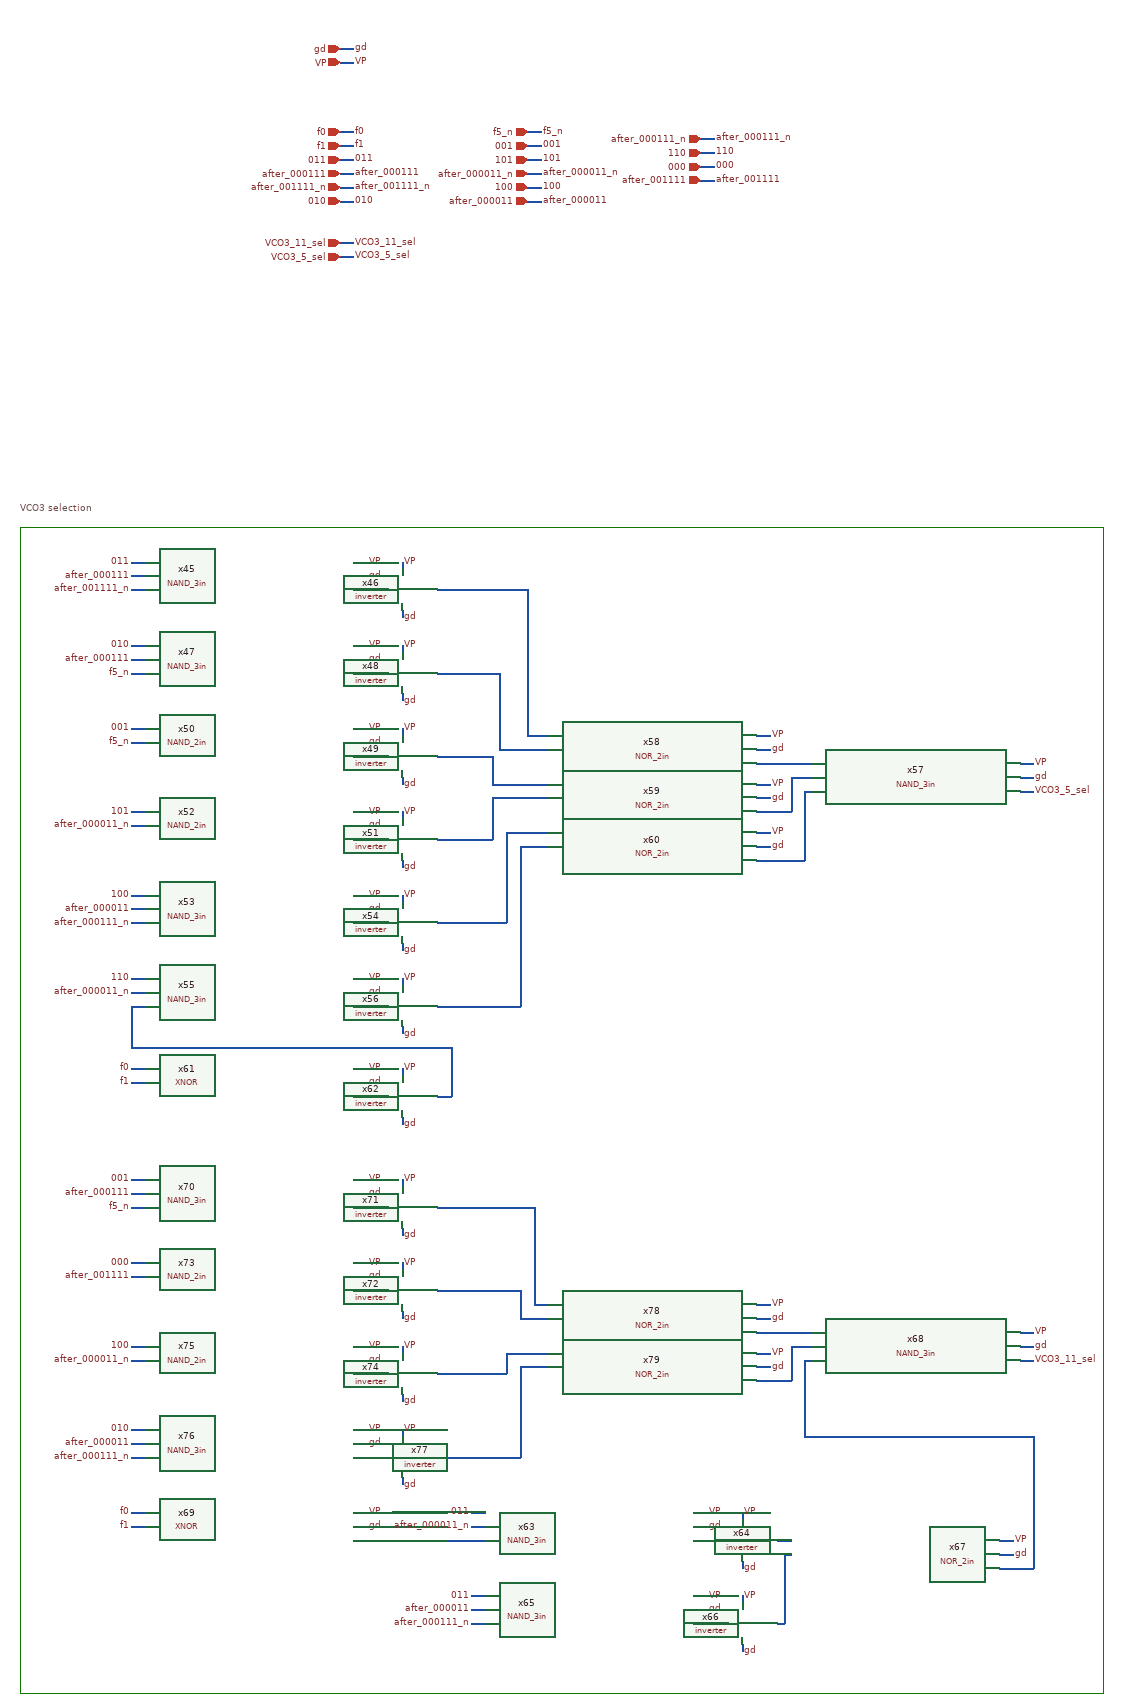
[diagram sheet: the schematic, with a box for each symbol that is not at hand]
v {xschem version=3.4.8RC file_version=1.3}
G {}
K {}
V {}
S {}
F {}
E {}
L 4 1210 -1360 1210 -1020 {}
L 4 1210 -1690 1210 -1350 {}
L 4 1210 -2030 1210 -1690 {}
L 4 1210 -2230 1210 -1890 {}
L 4 1210 -890 1210 -550 {}
L 4 1210 -1220 1210 -880 {}
L 4 1210 -1560 1210 -1220 {}
L 4 1210 -1760 1210 -1420 {}
L 4 2770 -2030 2770 -1690 {}
L 4 2770 -2230 2770 -1890 {}
L 4 2770 -890 2770 -550 {}
L 4 2770 -1220 2770 -880 {}
L 4 2770 -1560 2770 -1220 {}
L 4 2770 -1760 2770 -1420 {}
L 4 1210 -2230 1550 -2230 {}
L 4 1550 -2230 1890 -2230 {}
L 4 1880 -2230 2220 -2230 {}
L 4 2100 -2230 2440 -2230 {}
L 4 1540 -2230 1880 -2230 {}
L 4 1880 -2230 2220 -2230 {}
L 4 2210 -2230 2550 -2230 {}
L 4 2430 -2230 2770 -2230 {}
L 4 1210 -550 1550 -550 {}
L 4 1540 -550 1880 -550 {}
L 4 1880 -550 2220 -550 {}
L 4 2210 -550 2550 -550 {}
L 4 2430 -550 2770 -550 {}
T {VCO3 selection} 1210 -2270 0 0 0.4 0.4 {}
N 1690 -2160 1710 -2160 {lab=gd}
N 1690 -2180 1710 -2180 {lab=VP}
N 1760 -2110 1760 -2100 {lab=gd}
N 1760 -2180 1760 -2170 {lab=VP}
N 1690 -2140 1740 -2140 {lab=#net1}
N 1810 -2140 1940 -2140 {lab=#net2}
N 1370 -2180 1390 -2180 {lab=011}
N 1370 -2140 1390 -2140 {lab=after_001111_n}
N 1370 -2160 1390 -2160 {lab=after_000111}
N 1690 -2040 1710 -2040 {lab=gd}
N 1690 -2060 1710 -2060 {lab=VP}
N 1760 -1990 1760 -1980 {lab=gd}
N 1760 -2060 1760 -2050 {lab=VP}
N 1690 -2020 1740 -2020 {lab=#net3}
N 1810 -2020 1900 -2020 {lab=#net4}
N 1370 -2060 1390 -2060 {lab=010}
N 1370 -2020 1390 -2020 {lab=f5_n}
N 1370 -2040 1390 -2040 {lab=after_000111}
N 1690 -1920 1710 -1920 {lab=gd}
N 1690 -1940 1710 -1940 {lab=VP}
N 1760 -1870 1760 -1860 {lab=gd}
N 1760 -1940 1760 -1930 {lab=VP}
N 1690 -1900 1740 -1900 {lab=#net5}
N 1810 -1900 1890 -1900 {lab=#net6}
N 1370 -1940 1390 -1940 {lab=001}
N 1370 -1920 1390 -1920 {lab=f5_n}
N 1690 -1800 1710 -1800 {lab=gd}
N 1690 -1820 1710 -1820 {lab=VP}
N 1760 -1750 1760 -1740 {lab=gd}
N 1760 -1820 1760 -1810 {lab=VP}
N 1690 -1780 1740 -1780 {lab=#net7}
N 1810 -1780 1890 -1780 {lab=#net8}
N 1370 -1820 1390 -1820 {lab=101}
N 1370 -1800 1390 -1800 {lab=after_000011_n}
N 1690 -1680 1710 -1680 {lab=gd}
N 1690 -1700 1710 -1700 {lab=VP}
N 1760 -1630 1760 -1620 {lab=gd}
N 1760 -1700 1760 -1690 {lab=VP}
N 1690 -1660 1740 -1660 {lab=#net9}
N 1810 -1660 1910 -1660 {lab=#net10}
N 1370 -1700 1390 -1700 {lab=100}
N 1370 -1660 1390 -1660 {lab=after_000111_n}
N 1370 -1680 1390 -1680 {lab=after_000011}
N 1690 -1560 1710 -1560 {lab=gd}
N 1690 -1580 1710 -1580 {lab=VP}
N 1760 -1510 1760 -1500 {lab=gd}
N 1760 -1580 1760 -1570 {lab=VP}
N 1690 -1540 1740 -1540 {lab=#net11}
N 1370 -1580 1390 -1580 {lab=110}
N 1370 -1540 1390 -1540 {lab=#net12}
N 1370 -1560 1390 -1560 {lab=after_000011_n}
N 2270 -1910 2290 -1910 {lab=gd}
N 2270 -1930 2290 -1930 {lab=VP}
N 2270 -1840 2290 -1840 {lab=gd}
N 2270 -1860 2290 -1860 {lab=VP}
N 2270 -1770 2290 -1770 {lab=gd}
N 2270 -1790 2290 -1790 {lab=VP}
N 2650 -1870 2670 -1870 {lab=gd}
N 2650 -1890 2670 -1890 {lab=VP}
N 2270 -1890 2350 -1890 {lab=#net13}
N 2270 -1820 2320 -1820 {lab=#net14}
N 2320 -1870 2320 -1820 {lab=#net14}
N 2320 -1870 2350 -1870 {lab=#net14}
N 2340 -1850 2350 -1850 {lab=#net15}
N 2340 -1850 2340 -1750 {lab=#net15}
N 2270 -1750 2340 -1750 {lab=#net15}
N 2650 -1850 2670 -1850 {lab=VCO3_5_sel}
N 1890 -1860 1970 -1860 {lab=#net6}
N 1890 -1900 1890 -1860 {lab=#net6}
N 1890 -1840 1970 -1840 {lab=#net8}
N 1890 -1840 1890 -1780 {lab=#net8}
N 1910 -1790 1970 -1790 {lab=#net10}
N 1910 -1790 1910 -1660 {lab=#net10}
N 1810 -1540 1930 -1540 {lab=#net16}
N 1930 -1770 1930 -1540 {lab=#net16}
N 1930 -1770 1970 -1770 {lab=#net16}
N 1900 -1910 1970 -1910 {lab=#net4}
N 1900 -2020 1900 -1910 {lab=#net4}
N 1940 -2140 1940 -1930 {lab=#net2}
N 1940 -1930 1970 -1930 {lab=#net2}
N 1690 -1430 1710 -1430 {lab=gd}
N 1690 -1450 1710 -1450 {lab=VP}
N 1760 -1380 1760 -1370 {lab=gd}
N 1760 -1450 1760 -1440 {lab=VP}
N 1690 -1410 1740 -1410 {lab=#net17}
N 1810 -1410 1830 -1410 {lab=#net12}
N 1830 -1480 1830 -1410 {lab=#net12}
N 1370 -1480 1830 -1480 {lab=#net12}
N 1370 -1540 1370 -1480 {lab=#net12}
N 1370 -1450 1390 -1450 {lab=f0}
N 1370 -1430 1390 -1430 {lab=f1}
N 2180 -790 2200 -790 {lab=gd}
N 2180 -810 2200 -810 {lab=VP}
N 2250 -740 2250 -730 {lab=gd}
N 2250 -810 2250 -800 {lab=VP}
N 2180 -770 2230 -770 {lab=#net18}
N 2300 -770 2320 -770 {lab=#net19}
N 2180 -670 2200 -670 {lab=gd}
N 2180 -690 2200 -690 {lab=VP}
N 2250 -620 2250 -610 {lab=gd}
N 2250 -690 2250 -680 {lab=VP}
N 2180 -650 2230 -650 {lab=#net20}
N 2300 -650 2310 -650 {lab=#net21}
N 2620 -750 2640 -750 {lab=gd}
N 2620 -770 2640 -770 {lab=VP}
N 2620 -730 2670 -730 {lab=#net22}
N 2310 -750 2320 -750 {lab=#net21}
N 2310 -750 2310 -650 {lab=#net21}
N 1690 -790 1710 -790 {lab=gd}
N 1690 -810 1710 -810 {lab=VP}
N 1860 -690 1880 -690 {lab=011}
N 1860 -650 1880 -650 {lab=after_000111_n}
N 1860 -670 1880 -670 {lab=after_000011}
N 1370 -810 1390 -810 {lab=f0}
N 1370 -790 1390 -790 {lab=f1}
N 1860 -810 1880 -810 {lab=011}
N 1860 -790 1880 -790 {lab=after_000011_n}
N 1690 -770 1880 -770 {lab=#net23}
N 1690 -1270 1710 -1270 {lab=gd}
N 1690 -1290 1710 -1290 {lab=VP}
N 1760 -1220 1760 -1210 {lab=gd}
N 1760 -1290 1760 -1280 {lab=VP}
N 1690 -1250 1740 -1250 {lab=#net24}
N 1810 -1250 1950 -1250 {lab=#net25}
N 1370 -1290 1390 -1290 {lab=001}
N 1370 -1250 1390 -1250 {lab=f5_n}
N 1370 -1270 1390 -1270 {lab=after_000111}
N 1690 -1150 1710 -1150 {lab=gd}
N 1690 -1170 1710 -1170 {lab=VP}
N 1760 -1100 1760 -1090 {lab=gd}
N 1760 -1170 1760 -1160 {lab=VP}
N 1690 -1130 1740 -1130 {lab=#net26}
N 1810 -1130 1930 -1130 {lab=#net27}
N 1370 -1170 1390 -1170 {lab=000}
N 1370 -1150 1390 -1150 {lab=after_001111}
N 1690 -1030 1710 -1030 {lab=gd}
N 1690 -1050 1710 -1050 {lab=VP}
N 1760 -980 1760 -970 {lab=gd}
N 1760 -1050 1760 -1040 {lab=VP}
N 1690 -1010 1740 -1010 {lab=#net28}
N 1810 -1010 1910 -1010 {lab=#net29}
N 1370 -1050 1390 -1050 {lab=100}
N 1370 -1030 1390 -1030 {lab=after_000011_n}
N 1690 -910 1710 -910 {lab=gd}
N 1690 -930 1710 -930 {lab=VP}
N 1760 -860 1760 -850 {lab=gd}
N 1760 -930 1760 -920 {lab=VP}
N 1690 -890 1740 -890 {lab=#net30}
N 1810 -890 1930 -890 {lab=#net31}
N 1370 -930 1390 -930 {lab=010}
N 1370 -890 1390 -890 {lab=after_000111_n}
N 1370 -910 1390 -910 {lab=after_000011}
N 2270 -1090 2290 -1090 {lab=gd}
N 2270 -1110 2290 -1110 {lab=VP}
N 2270 -1020 2290 -1020 {lab=gd}
N 2270 -1040 2290 -1040 {lab=VP}
N 2650 -1050 2670 -1050 {lab=gd}
N 2650 -1070 2670 -1070 {lab=VP}
N 2270 -1070 2350 -1070 {lab=#net32}
N 2270 -1000 2320 -1000 {lab=#net33}
N 2320 -1050 2320 -1000 {lab=#net33}
N 2320 -1050 2350 -1050 {lab=#net33}
N 2340 -1030 2350 -1030 {lab=#net22}
N 2340 -1030 2340 -920 {lab=#net22}
N 2650 -1030 2670 -1030 {lab=VCO3_11_sel}
N 2670 -920 2670 -730 {lab=#net22}
N 2340 -920 2670 -920 {lab=#net22}
N 1950 -1250 1950 -1110 {lab=#net25}
N 1950 -1110 1970 -1110 {lab=#net25}
N 1930 -1090 1970 -1090 {lab=#net27}
N 1930 -1130 1930 -1090 {lab=#net27}
N 1910 -1040 1910 -1010 {lab=#net29}
N 1910 -1040 1970 -1040 {lab=#net29}
N 1930 -1020 1970 -1020 {lab=#net31}
N 1930 -1020 1930 -890 {lab=#net31}
N 1670 -2920 1690 -2920 {lab=gd}
N 1670 -2900 1690 -2900 {lab=VP}
N 1670 -2800 1690 -2800 {lab=f0}
N 1670 -2780 1690 -2780 {lab=f1}
N 1670 -2640 1690 -2640 {lab=VCO3_11_sel}
N 1670 -2620 1690 -2620 {lab=VCO3_5_sel}
N 1670 -2760 1690 -2760 {lab=011}
N 1670 -2740 1690 -2740 {lab=after_000111}
N 1670 -2720 1690 -2720 {lab=after_001111_n}
N 1670 -2700 1690 -2700 {lab=010}
N 1940 -2780 1960 -2780 {lab=001}
N 1940 -2760 1960 -2760 {lab=101}
N 1940 -2800 1960 -2800 {lab=f5_n}
N 1940 -2720 1960 -2720 {lab=100}
N 1940 -2700 1960 -2700 {lab=after_000011}
N 1940 -2740 1960 -2740 {lab=after_000011_n}
N 2190 -2770 2210 -2770 {lab=110}
N 2190 -2750 2210 -2750 {lab=000}
N 2190 -2790 2210 -2790 {lab=after_000111_n}
N 2190 -2730 2210 -2730 {lab=after_001111}
C {NAND_3in.sym} 1540 -2160 0 0 {name=x45}
C {lab_wire.sym} 1710 -2180 2 0 {name=p221 sig_type=std_logic lab=VP}
C {lab_wire.sym} 1710 -2160 2 0 {name=p222 sig_type=std_logic lab=gd}
C {inverter.sym} 1760 -2140 0 0 {name=x46}
C {lab_wire.sym} 1760 -2180 0 1 {name=p223 sig_type=std_logic lab=VP}
C {lab_wire.sym} 1760 -2100 2 0 {name=p224 sig_type=std_logic lab=gd}
C {NAND_3in.sym} 1540 -2040 0 0 {name=x47}
C {lab_wire.sym} 1710 -2060 2 0 {name=p225 sig_type=std_logic lab=VP}
C {lab_wire.sym} 1710 -2040 2 0 {name=p226 sig_type=std_logic lab=gd}
C {inverter.sym} 1760 -2020 0 0 {name=x48}
C {lab_wire.sym} 1760 -2060 0 1 {name=p227 sig_type=std_logic lab=VP}
C {lab_wire.sym} 1760 -1980 2 0 {name=p228 sig_type=std_logic lab=gd}
C {lab_wire.sym} 1710 -1940 2 0 {name=p229 sig_type=std_logic lab=VP}
C {lab_wire.sym} 1710 -1920 2 0 {name=p230 sig_type=std_logic lab=gd}
C {inverter.sym} 1760 -1900 0 0 {name=x49}
C {lab_wire.sym} 1760 -1940 0 1 {name=p231 sig_type=std_logic lab=VP}
C {lab_wire.sym} 1760 -1860 2 0 {name=p232 sig_type=std_logic lab=gd}
C {NAND_2in.sym} 1540 -1920 0 0 {name=x50}
C {lab_wire.sym} 1710 -1820 2 0 {name=p233 sig_type=std_logic lab=VP}
C {lab_wire.sym} 1710 -1800 2 0 {name=p234 sig_type=std_logic lab=gd}
C {inverter.sym} 1760 -1780 0 0 {name=x51}
C {lab_wire.sym} 1760 -1820 0 1 {name=p235 sig_type=std_logic lab=VP}
C {lab_wire.sym} 1760 -1740 2 0 {name=p236 sig_type=std_logic lab=gd}
C {NAND_2in.sym} 1540 -1800 0 0 {name=x52}
C {NAND_3in.sym} 1540 -1680 0 0 {name=x53}
C {lab_wire.sym} 1710 -1700 2 0 {name=p237 sig_type=std_logic lab=VP}
C {lab_wire.sym} 1710 -1680 2 0 {name=p238 sig_type=std_logic lab=gd}
C {inverter.sym} 1760 -1660 0 0 {name=x54}
C {lab_wire.sym} 1760 -1700 0 1 {name=p239 sig_type=std_logic lab=VP}
C {lab_wire.sym} 1760 -1620 2 0 {name=p240 sig_type=std_logic lab=gd}
C {NAND_3in.sym} 1540 -1560 0 0 {name=x55}
C {lab_wire.sym} 1710 -1580 2 0 {name=p241 sig_type=std_logic lab=VP}
C {lab_wire.sym} 1710 -1560 2 0 {name=p242 sig_type=std_logic lab=gd}
C {inverter.sym} 1760 -1540 0 0 {name=x56}
C {lab_wire.sym} 1760 -1580 0 1 {name=p243 sig_type=std_logic lab=VP}
C {lab_wire.sym} 1760 -1500 2 0 {name=p244 sig_type=std_logic lab=gd}
C {NAND_3in.sym} 2500 -1870 0 0 {name=x57}
C {NOR_2in.sym} 2120 -1910 0 0 {name=x58}
C {lab_wire.sym} 2290 -1930 2 0 {name=p245 sig_type=std_logic lab=VP}
C {lab_wire.sym} 2290 -1910 2 0 {name=p246 sig_type=std_logic lab=gd}
C {NOR_2in.sym} 2120 -1840 0 0 {name=x59}
C {lab_wire.sym} 2290 -1860 2 0 {name=p247 sig_type=std_logic lab=VP}
C {lab_wire.sym} 2290 -1840 2 0 {name=p248 sig_type=std_logic lab=gd}
C {NOR_2in.sym} 2120 -1770 0 0 {name=x60}
C {lab_wire.sym} 2290 -1790 2 0 {name=p249 sig_type=std_logic lab=VP}
C {lab_wire.sym} 2290 -1770 2 0 {name=p250 sig_type=std_logic lab=gd}
C {lab_wire.sym} 2670 -1890 2 0 {name=p251 sig_type=std_logic lab=VP}
C {lab_wire.sym} 2670 -1870 2 0 {name=p252 sig_type=std_logic lab=gd}
C {lab_wire.sym} 1370 -2180 0 0 {name=p253 sig_type=std_logic lab=011}
C {lab_wire.sym} 1370 -2060 0 0 {name=p254 sig_type=std_logic lab=010}
C {lab_wire.sym} 1370 -1940 0 0 {name=p255 sig_type=std_logic lab=001}
C {lab_wire.sym} 1370 -1820 0 0 {name=p256 sig_type=std_logic lab=101}
C {lab_wire.sym} 1370 -1580 0 0 {name=p257 sig_type=std_logic lab=110}
C {lab_wire.sym} 1370 -1700 0 0 {name=p258 sig_type=std_logic lab=100}
C {XNOR.sym} 1540 -1430 0 0 {name=x61}
C {lab_wire.sym} 1710 -1450 2 0 {name=p259 sig_type=std_logic lab=VP}
C {lab_wire.sym} 1710 -1430 2 0 {name=p260 sig_type=std_logic lab=gd}
C {inverter.sym} 1760 -1410 0 0 {name=x62}
C {lab_wire.sym} 1760 -1450 0 1 {name=p261 sig_type=std_logic lab=VP}
C {lab_wire.sym} 1760 -1370 2 0 {name=p262 sig_type=std_logic lab=gd}
C {lab_wire.sym} 1370 -2160 0 0 {name=p263 sig_type=std_logic lab=after_000111}
C {lab_wire.sym} 1370 -2140 0 0 {name=p264 sig_type=std_logic lab=after_001111_n}
C {lab_wire.sym} 1370 -2040 0 0 {name=p265 sig_type=std_logic lab=after_000111}
C {lab_wire.sym} 1370 -2020 0 0 {name=p266 sig_type=std_logic lab=f5_n}
C {lab_wire.sym} 1370 -1920 0 0 {name=p267 sig_type=std_logic lab=f5_n}
C {lab_wire.sym} 1370 -1800 0 0 {name=p268 sig_type=std_logic lab=after_000011_n}
C {lab_wire.sym} 1370 -1680 0 0 {name=p269 sig_type=std_logic lab=after_000011}
C {lab_wire.sym} 1370 -1660 0 0 {name=p270 sig_type=std_logic lab=after_000111_n}
C {lab_wire.sym} 1370 -1560 0 0 {name=p271 sig_type=std_logic lab=after_000011_n}
C {lab_wire.sym} 1370 -1450 0 0 {name=p272 sig_type=std_logic lab=f0}
C {lab_wire.sym} 1370 -1430 0 0 {name=p273 sig_type=std_logic lab=f1}
C {lab_wire.sym} 2670 -1850 2 0 {name=p274 sig_type=std_logic lab=VCO3_5_sel}
C {NAND_3in.sym} 2030 -790 0 0 {name=x63}
C {lab_wire.sym} 2200 -810 2 0 {name=p275 sig_type=std_logic lab=VP}
C {lab_wire.sym} 2200 -790 2 0 {name=p276 sig_type=std_logic lab=gd}
C {inverter.sym} 2250 -770 0 0 {name=x64}
C {lab_wire.sym} 2250 -810 0 1 {name=p277 sig_type=std_logic lab=VP}
C {lab_wire.sym} 2250 -730 2 0 {name=p278 sig_type=std_logic lab=gd}
C {NAND_3in.sym} 2030 -670 0 0 {name=x65}
C {lab_wire.sym} 2200 -690 2 0 {name=p279 sig_type=std_logic lab=VP}
C {lab_wire.sym} 2200 -670 2 0 {name=p280 sig_type=std_logic lab=gd}
C {inverter.sym} 2250 -650 0 0 {name=x66}
C {lab_wire.sym} 2250 -690 0 1 {name=p281 sig_type=std_logic lab=VP}
C {lab_wire.sym} 2250 -610 2 0 {name=p282 sig_type=std_logic lab=gd}
C {NOR_2in.sym} 2470 -750 0 0 {name=x67}
C {lab_wire.sym} 2640 -770 2 0 {name=p283 sig_type=std_logic lab=VP}
C {lab_wire.sym} 2640 -750 2 0 {name=p284 sig_type=std_logic lab=gd}
C {XNOR.sym} 1540 -790 0 0 {name=x69}
C {lab_wire.sym} 1710 -810 2 0 {name=p287 sig_type=std_logic lab=VP}
C {lab_wire.sym} 1710 -790 2 0 {name=p288 sig_type=std_logic lab=gd}
C {NAND_3in.sym} 1540 -1270 0 0 {name=x70}
C {lab_wire.sym} 1710 -1290 2 0 {name=p289 sig_type=std_logic lab=VP}
C {lab_wire.sym} 1710 -1270 2 0 {name=p290 sig_type=std_logic lab=gd}
C {inverter.sym} 1760 -1250 0 0 {name=x71}
C {lab_wire.sym} 1760 -1290 0 1 {name=p291 sig_type=std_logic lab=VP}
C {lab_wire.sym} 1760 -1210 2 0 {name=p292 sig_type=std_logic lab=gd}
C {lab_wire.sym} 1710 -1170 2 0 {name=p293 sig_type=std_logic lab=VP}
C {lab_wire.sym} 1710 -1150 2 0 {name=p294 sig_type=std_logic lab=gd}
C {inverter.sym} 1760 -1130 0 0 {name=x72}
C {lab_wire.sym} 1760 -1170 0 1 {name=p295 sig_type=std_logic lab=VP}
C {lab_wire.sym} 1760 -1090 2 0 {name=p296 sig_type=std_logic lab=gd}
C {NAND_2in.sym} 1540 -1150 0 0 {name=x73}
C {lab_wire.sym} 1710 -1050 2 0 {name=p297 sig_type=std_logic lab=VP}
C {lab_wire.sym} 1710 -1030 2 0 {name=p298 sig_type=std_logic lab=gd}
C {inverter.sym} 1760 -1010 0 0 {name=x74}
C {lab_wire.sym} 1760 -1050 0 1 {name=p299 sig_type=std_logic lab=VP}
C {lab_wire.sym} 1760 -970 2 0 {name=p300 sig_type=std_logic lab=gd}
C {NAND_2in.sym} 1540 -1030 0 0 {name=x75}
C {NAND_3in.sym} 1540 -910 0 0 {name=x76}
C {lab_wire.sym} 1710 -930 2 0 {name=p301 sig_type=std_logic lab=VP}
C {lab_wire.sym} 1710 -910 2 0 {name=p302 sig_type=std_logic lab=gd}
C {inverter.sym} 1760 -890 0 0 {name=x77}
C {lab_wire.sym} 1760 -930 0 1 {name=p303 sig_type=std_logic lab=VP}
C {lab_wire.sym} 1760 -850 2 0 {name=p304 sig_type=std_logic lab=gd}
C {NAND_3in.sym} 2500 -1050 0 0 {name=x68}
C {NOR_2in.sym} 2120 -1090 0 0 {name=x78}
C {lab_wire.sym} 2290 -1110 2 0 {name=p285 sig_type=std_logic lab=VP}
C {lab_wire.sym} 2290 -1090 2 0 {name=p286 sig_type=std_logic lab=gd}
C {NOR_2in.sym} 2120 -1020 0 0 {name=x79}
C {lab_wire.sym} 2290 -1040 2 0 {name=p305 sig_type=std_logic lab=VP}
C {lab_wire.sym} 2290 -1020 2 0 {name=p306 sig_type=std_logic lab=gd}
C {lab_wire.sym} 2670 -1070 2 0 {name=p309 sig_type=std_logic lab=VP}
C {lab_wire.sym} 2670 -1050 2 0 {name=p310 sig_type=std_logic lab=gd}
C {lab_wire.sym} 1370 -1290 0 0 {name=p307 sig_type=std_logic lab=001}
C {lab_wire.sym} 1370 -1170 0 0 {name=p308 sig_type=std_logic lab=000}
C {lab_wire.sym} 1370 -1050 0 0 {name=p311 sig_type=std_logic lab=100}
C {lab_wire.sym} 1370 -930 0 0 {name=p312 sig_type=std_logic lab=010}
C {lab_wire.sym} 1860 -810 0 0 {name=p313 sig_type=std_logic lab=011}
C {lab_wire.sym} 1860 -690 0 0 {name=p314 sig_type=std_logic lab=011}
C {lab_wire.sym} 1370 -1270 0 0 {name=p315 sig_type=std_logic lab=after_000111}
C {lab_wire.sym} 1370 -1250 0 0 {name=p316 sig_type=std_logic lab=f5_n}
C {lab_wire.sym} 1370 -1150 0 0 {name=p317 sig_type=std_logic lab=after_001111}
C {lab_wire.sym} 1370 -1030 0 0 {name=p318 sig_type=std_logic lab=after_000011_n}
C {lab_wire.sym} 1370 -910 0 0 {name=p319 sig_type=std_logic lab=after_000011}
C {lab_wire.sym} 1370 -890 0 0 {name=p320 sig_type=std_logic lab=after_000111_n}
C {lab_wire.sym} 1370 -810 0 0 {name=p321 sig_type=std_logic lab=f0}
C {lab_wire.sym} 1370 -790 0 0 {name=p322 sig_type=std_logic lab=f1}
C {lab_wire.sym} 1860 -790 0 0 {name=p323 sig_type=std_logic lab=after_000011_n}
C {lab_wire.sym} 1860 -670 0 0 {name=p324 sig_type=std_logic lab=after_000011}
C {lab_wire.sym} 1860 -650 0 0 {name=p325 sig_type=std_logic lab=after_000111_n}
C {lab_wire.sym} 2670 -1030 2 0 {name=p326 sig_type=std_logic lab=VCO3_11_sel}
C {iopin.sym} 1670 -2920 2 0 {name=p46 lab=gd}
C {lab_wire.sym} 1690 -2920 2 0 {name=p53 sig_type=std_logic lab=gd}
C {iopin.sym} 1670 -2900 2 0 {name=p54 lab=VP}
C {ipin.sym} 1670 -2800 0 0 {name=p59 lab=f0}
C {lab_wire.sym} 1690 -2800 2 0 {name=p60 sig_type=std_logic lab=f0}
C {ipin.sym} 1670 -2780 0 0 {name=p61 lab=f1}
C {lab_wire.sym} 1690 -2780 2 0 {name=p63 sig_type=std_logic lab=f1}
C {lab_wire.sym} 1690 -2900 2 0 {name=p1 sig_type=std_logic lab=VP}
C {opin.sym} 1670 -2640 0 1 {name=p6 lab=VCO3_11_sel}
C {lab_wire.sym} 1690 -2640 2 0 {name=p7 sig_type=std_logic lab=VCO3_11_sel}
C {opin.sym} 1670 -2620 0 1 {name=p8 lab=VCO3_5_sel}
C {lab_wire.sym} 1690 -2620 2 0 {name=p9 sig_type=std_logic lab=VCO3_5_sel}
C {ipin.sym} 1670 -2760 0 0 {name=p19 lab=011}
C {lab_wire.sym} 1690 -2760 2 0 {name=p22 sig_type=std_logic lab=011}
C {ipin.sym} 1670 -2740 0 0 {name=p23 lab=after_000111}
C {lab_wire.sym} 1690 -2740 2 0 {name=p24 sig_type=std_logic lab=after_000111}
C {ipin.sym} 1670 -2720 0 0 {name=p25 lab=after_001111_n}
C {lab_wire.sym} 1690 -2720 2 0 {name=p26 sig_type=std_logic lab=after_001111_n}
C {ipin.sym} 1670 -2700 0 0 {name=p27 lab=010}
C {lab_wire.sym} 1690 -2700 2 0 {name=p28 sig_type=std_logic lab=010}
C {ipin.sym} 1940 -2780 0 0 {name=p3 lab=001}
C {lab_wire.sym} 1960 -2780 2 0 {name=p4 sig_type=std_logic lab=001}
C {ipin.sym} 1940 -2760 0 0 {name=p5 lab=101}
C {lab_wire.sym} 1960 -2760 2 0 {name=p10 sig_type=std_logic lab=101}
C {ipin.sym} 1940 -2800 0 0 {name=p11 lab=f5_n}
C {lab_wire.sym} 1960 -2800 2 0 {name=p12 sig_type=std_logic lab=f5_n}
C {ipin.sym} 1940 -2720 0 0 {name=p13 lab=100}
C {lab_wire.sym} 1960 -2720 2 0 {name=p14 sig_type=std_logic lab=100}
C {ipin.sym} 1940 -2700 0 0 {name=p15 lab=after_000011}
C {lab_wire.sym} 1960 -2700 2 0 {name=p16 sig_type=std_logic lab=after_000011}
C {ipin.sym} 1940 -2740 0 0 {name=p17 lab=after_000011_n}
C {lab_wire.sym} 1960 -2740 2 0 {name=p18 sig_type=std_logic lab=after_000011_n}
C {ipin.sym} 2190 -2770 0 0 {name=p29 lab=110}
C {lab_wire.sym} 2210 -2770 2 0 {name=p30 sig_type=std_logic lab=110}
C {ipin.sym} 2190 -2750 0 0 {name=p31 lab=000}
C {lab_wire.sym} 2210 -2750 2 0 {name=p32 sig_type=std_logic lab=000}
C {ipin.sym} 2190 -2790 0 0 {name=p33 lab=after_000111_n}
C {lab_wire.sym} 2210 -2790 2 0 {name=p34 sig_type=std_logic lab=after_000111_n}
C {ipin.sym} 2190 -2730 0 0 {name=p39 lab=after_001111}
C {lab_wire.sym} 2210 -2730 2 0 {name=p40 sig_type=std_logic lab=after_001111}
